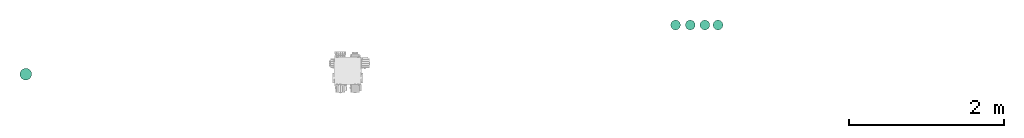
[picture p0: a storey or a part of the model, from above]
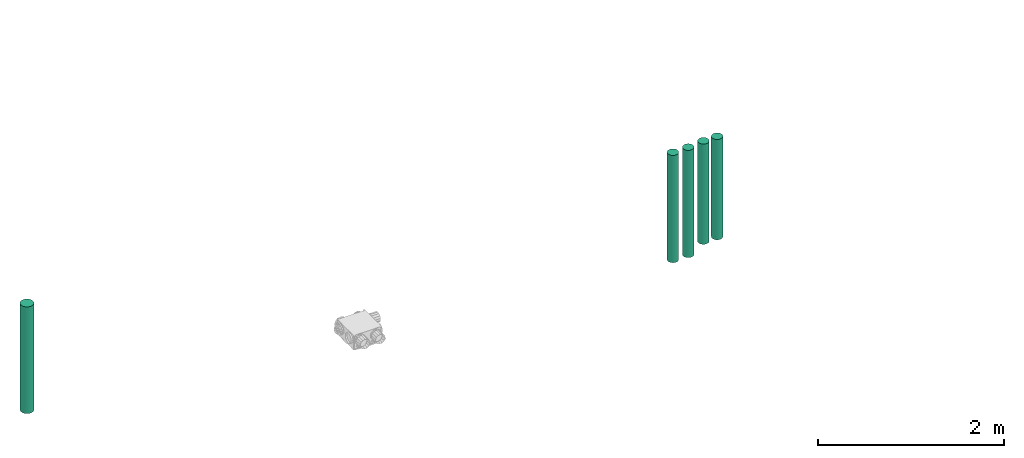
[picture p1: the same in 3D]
Properties of the parts of a building model (IFC4)

# File
Description: ViewDefinition [ReferenceView_V1.1]
File name: Project Number
Time: 2024-09-24T10:27:24
Written by: The EXPRESS Data Manager Version 5.02.0100.07 : 28 Aug 2013
Made in: 20191106_1200(x64) - Exporter 20.2.1.1 - Alternate UI 20.2.1.1
Comment: STEP Physical File produced by: The EXPRESS Data Manager Version 5.02.0100.07 : 28 Aug 2013 * Module: EDMstepFileFactory/EDMstandAlone * Creation date: Tue Sep 24 10:27:24 2024 * Host: RENSON-PC64rjMe * Database: C:\Users\naniw\AppData\Local\Temp\34e044a4-42ef-4c0d-bd3a-4a185e34024d\e22b095f-4d8d-4bd7-b097-9bfb5491500f\ifc * Database version: 5507 * Database creation date: Tue Sep 24 10:27:12 2024 * Schema: IFC4 * Model: DataRepository.ifc * Model creation date: Tue Sep 24 10:27:12 2024 * Header model: DataRepository.ifc_HeaderModel * Header model creation date: Tue Sep 24 10:27:12 2024 * EDMuser: sdai-user * EDMgroup: sdai-group * License ID and type: 5605 : Permanent license. Expiry date: * EDMstepFileFactory options: 020000

# IfcProject, Project Number
LongName: Project Name; Phase: Project Status

# IfcSite, Default
RefLatitude: 42, 12, 46, 799999; RefLongitude: -71, -1, -58, -799999; RefElevation: 0 mm

# IfcBuilding
Pset_BuildingCommon - Reference: Project Information; NumberOfStoreys: 4

# IfcBuildingStorey: Level:8mm Head (4)
Pset_BuildingStoreyCommon - Reference: 8mm Head
Name | LongName | Elevation (mm)
Level 1x | Level 1x | 0
Level 1 | Level 1 | 113.902
Position HB3 | Position HB3 | 1750
Level 1y | Level 1y | 2313.9

# IfcAirTerminalBox: Healthbox 3.0 - ceiling, Renson_Healthbox 3 Hygro+_Extraction_Unit:Healthbox 3.0 - ceiling:1049261
In: Position HB3
Type - Material: Color RGB 037-040-080, Color RGB 255-255-255
Type - Pset_AirTerminalBoxTypeCommon - Reference: Healthbox 3.0 - ceiling
Type - Pset_EnvironmentalImpactIndicators - Reference: Healthbox 3.0 - ceiling
Type - Pset_ManufacturerTypeInformation - Manufacturer: Renson
Pset_AirTerminalBoxTypeCommon - sets with these values: 2

# IfcAirTerminalBox: Healthbox 3.0 - wall attiek, Renson_Healthbox 3 Hygro+_Extraction_Unit:Healthbox 3.0 - wall attiek:1049051
In: Level 1x
Type - Material: Color RGB 037-040-080, Color RGB 255-255-255
Type - Pset_AirTerminalBoxTypeCommon - Reference: Healthbox 3.0 - wall attiek
Type - Pset_EnvironmentalImpactIndicators - Reference: Healthbox 3.0 - wall attiek
Type - Pset_ManufacturerTypeInformation - Manufacturer: Renson
Pset_AirTerminalBoxTypeCommon - sets with these values: 2

# IfcAirTerminalBox: Healthbox 3.0 - wall attiek 2, Renson_Healthbox 3 Hygro+_Extraction_Unit:Healthbox 3.0 - wall attiek 2:1060601
In: Level 1x
Type - Material: Color RGB 037-040-080, Color RGB 255-255-255
Type - Pset_AirTerminalBoxTypeCommon - Reference: Healthbox 3.0 - wall attiek 2
Type - Pset_EnvironmentalImpactIndicators - Reference: Healthbox 3.0 - wall attiek 2
Type - Pset_ManufacturerTypeInformation - Manufacturer: Renson
Pset_AirTerminalBoxTypeCommon - sets with these values: 2

# IfcAirTerminalBox: Healthbox 3.0 - wall wc (2)
Type - Material: Color RGB 037-040-080, Color RGB 255-255-255
Type - Pset_AirTerminalBoxTypeCommon - Reference: Healthbox 3.0 - wall wc
Type - Pset_EnvironmentalImpactIndicators - Reference: Healthbox 3.0 - wall wc
Type - Pset_ManufacturerTypeInformation - Manufacturer: Renson
Pset_AirTerminalBoxTypeCommon - sets with these values: 2
Name (Renson_Healthbox 3 Hygro+_Extraction_Unit:Healthbox 3.0 - wall wc:...) | In
1022833 | Level 1x
1059578 | Level 1

# IfcBuildingElementProxy: Model Text:120mm Arial (5)
In: Level 1x
Pset_BuildingElementProxyCommon - IsExternal: no; Reference: 120mm Arial
Pset_BuildingElementProxyProvisionForVoid - Depth: 10 mm
Pset_EnvironmentalImpactIndicators - Reference: 120mm Arial
Name (Model Text:120mm Arial:...) | Width (mm) | Height (mm)
1086742 | 10 | 15.0684
1086753 | 10 | 15.0684
1086783 | 10 | 15.0684
1086848 | 10 | 15.0684
1086858

# IfcBuildingElementProxy: Model Text:190mm Arial (5)
In: Level 1x
Pset_BuildingElementProxyCommon - Reference: 190mm Arial; IsExternal: no
Pset_BuildingElementProxyProvisionForVoid - Depth: 10 mm
Pset_EnvironmentalImpactIndicators - Reference: 190mm Arial
Name (Model Text:190mm Arial:...) | Width (mm) | Height (mm)
1086664 | 10 | 23.8584
1086681 | 10 | 23.8584
1086690 | 10 | 23.8584
1086699 | 10 | 23.8584
1086710

# IfcController: Bathroom Module (28)
Type - Classification: ﻿﻿ ​ ​ ​ ﻿ ​ ​ ﻿ ​ ​ ﻿ ​﻿ ​ ​ ﻿ ﻿﻿ (Uniformat); Material: Color RGB 037-040-080, Color RGB 255-255-255, Color RGB 040-040-040
Type - Pset_ControllerTypeCommon - Reference: Bathroom Module
Type - Pset_EnvironmentalImpactIndicators - Reference: Bathroom Module
Type - Pset_ManufacturerTypeInformation - Manufacturer: Renson
Pset_ControllerTypeCommon - sets with these values: 2
Name (Renson_Healthbox 3 Hygro+_Control Unit_Control Module:Bathroom Module:...) | In
1023607 | Level 1x
1032259 | Level 1x
1033093 | Level 1x
1033628 | Position HB3
1034343 | Level 1x
1034346 | Level 1x
1049052 | Level 1x
1049053 | Level 1x
1049262 | Position HB3
1049263 | Position HB3
1051230 | Position HB3
1052670 | Level 1y
1053146 | Level 1y
1053752 | Level 1x
1054423 | Level 1x
1059581 | Position HB3
1059586 | Level 1x
1059587 | Level 1x
1059600 | Level 1
1059601 | Level 1
1059943 | Level 1x
1081952 | Level 1x
1083636 | Level 1x
1083668 | Level 1x
1084480 | Level 1x
1084481 | Level 1x
1094915 | Level 1x
1094946 | Level 1x

# IfcCovering: Compound Ceiling:Plain (3)
In: Level 1
Type - PredefinedType: CEILING
Type - Pset_CoveringCommon - IsExternal: no; Reference: Plain; ThermalTransmittance: 0.549915 kg/K/s3
Type - Pset_EnvironmentalImpactIndicators - Reference: Plain
Material: Metal Stud Layer 45 mm, Gypsum Wall Board 12 mm; Group: Model Group:Renson_Ceiling_01 (members excluded):1088081
Name (Compound Ceiling:Plain:...)
1088362
1088379
1088469

# IfcCovering: Compound Ceiling:Transparent, Compound Ceiling:Transparent:1088462
In: Level 1
Type - PredefinedType: CEILING
Type - Pset_CoveringCommon - IsExternal: no; Reference: Transparent; ThermalTransmittance: 19.2982 kg/K/s3
Type - Pset_EnvironmentalImpactIndicators - Reference: Transparent
Material: Glass, Clear Glazing 57 mm; Group: Model Group:Renson_Ceiling_01 (members excluded):1088081

# IfcDuctFitting: 1.5 D (5)
In: Level 1x
Type - Pset_DuctFittingTypeCommon - Reference: 1.5 D
Type - Pset_EnvironmentalImpactIndicators - Reference: 1.5 D
Pset_DuctFittingTypeCommon - sets with these values: 2
Name (M_Round Elbow:1.5 D:...)
1048279
1059492
1059612
1064223
1086076

# IfcDuctFitting: 125 (2)
In: Level 1x
Type - Classification: ﻿﻿​ ﻿﻿﻿ ﻿ ﻿ ﻿ ﻿ ﻿ ﻿ ﻿ ﻿ ﻿ ﻿ ﻿ ​ ﻿ ﻿ ​ ​ ﻿ ﻿ ​﻿﻿ (Uniformat); Material: Color RGB 037-040-080
Type - Pset_DuctFittingTypeCommon - Reference: 125
Type - Pset_EnvironmentalImpactIndicators - Reference: 125
Type - Pset_ManufacturerTypeInformation - Manufacturer: Renson
Pset_DuctFittingTypeCommon - sets with these values: 2
Name
Renson_Easyflex_Round_Coupling_S:125:1080404
VE_Coupling_Round_MEPcontent_Renson_Easyflex_BE-EN_CP Shared:125:1081115

# IfcDuctFitting: 125 (2)
In: Level 1x
Type - PredefinedType: TRANSITION; Material: Color RAL 9002
Type - Pset_DuctFittingTypeCommon - Reference: 125
Type - Pset_EnvironmentalImpactIndicators - Reference: 125
Type - Pset_ManufacturerTypeInformation - Manufacturer: Renson
Pset_DuctFittingTypeCommon - sets with these values: 2
Name
Renson_Easyflex_Reducer_Oval to Round:125:1080402
Renson_Easyflex_Connection Piece_Oval to Round:125:1081114

# IfcDuctFitting: 125-150 (5)
Type - PredefinedType: TRANSITION; Classification: ﻿﻿ ​ ​ ​ ﻿ ​ ​ ﻿ ​ ​ ﻿ ​﻿ ​ ​ ﻿ ﻿﻿ (Uniformat); Material: Color RGB 037-040-080
Type - Pset_DuctFittingTypeCommon - Reference: 125-150
Type - Pset_EnvironmentalImpactIndicators - Reference: 125-150
Type - Pset_ManufacturerTypeInformation - Manufacturer: Renson
Pset_DuctFittingTypeCommon - sets with these values: 2
Name (Renson_Healthbox 3_Reducer_Round_Exhaust Adapter 125-150:125-150:...) | In
1022835 | Level 1x
1049055 | Level 1x
1049265 | Position HB3
1059579 | Position HB3
1060605 | Level 1x

# IfcDuctFitting: 135x55 Flat (4)
In: Level 1x
Type - Classification: ﻿﻿​ ﻿﻿﻿ ﻿ ﻿ ﻿ ﻿ ﻿ ﻿ ﻿ ﻿ ﻿ ﻿ ﻿ ​ ﻿ ﻿ ​ ​ ﻿ ﻿ ​﻿﻿ (Uniformat); Material: Color RGB 037-040-080
Type - Pset_DuctFittingTypeCommon - Reference: 135x55 Flat
Type - Pset_EnvironmentalImpactIndicators - Reference: 135x55 Flat
Type - Pset_ManufacturerTypeInformation - Manufacturer: Renson
Pset_DuctFittingTypeCommon - sets with these values: 2
Name
VE_Coupling_Oval_MEPcontent_Renson_Easyflex_Flat_BE-EN_CP Shared:135x55 Flat:1042776
VE_Coupling_Oval_MEPcontent_Renson_Easyflex_Flat_BE-EN_CP Shared:135x55 Flat:1059604
Renson_Easyflex_Flat_Coupling_Oval_S:135x55 Flat:1080403
VE_Coupling_Oval_MEPcontent_Renson_Easyflex_Flat_BE-EN_CP Shared:135x55 Flat:1081116

# IfcDuctFitting: 135x55 Quick Bracket (8)
In: Level 1x
Type - Material: Color RGB 037-040-080
Type - Pset_DuctFittingTypeCommon - Reference: 135x55 Quick Bracket
Type - Pset_EnvironmentalImpactIndicators - Reference: 135x55 Quick Bracket
Type - Pset_ManufacturerTypeInformation - Manufacturer: Renson
Pset_DuctFittingTypeCommon - sets with these values: 2
Name
VE_Bracket_MEPcontent_Renson_Easyflex_Quick_BE-EN_CP Shared:135x55 Quick Bracket:1042777
VE_Bracket_MEPcontent_Renson_Easyflex_Quick_BE-EN_CP Shared:135x55 Quick Bracket:1042778
VE_Bracket_MEPcontent_Renson_Easyflex_Quick_BE-EN_CP Shared:135x55 Quick Bracket:1059605
VE_Bracket_MEPcontent_Renson_Easyflex_Quick_BE-EN_CP Shared:135x55 Quick Bracket:1059606
Renson_Easyflex_Quick_Bracket_S:135x55 Quick Bracket:1080405
Renson_Easyflex_Quick_Bracket_S:135x55 Quick Bracket:1080406
VE_Bracket_MEPcontent_Renson_Easyflex_Quick_BE-EN_CP Shared:135x55 Quick Bracket:1081117
VE_Bracket_MEPcontent_Renson_Easyflex_Quick_BE-EN_CP Shared:135x55 Quick Bracket:1081118

# IfcDuctFitting: 80 (2)
In: Level 1x
Type - Classification: ﻿﻿​ ﻿﻿﻿ ﻿ ﻿ ﻿ ﻿ ﻿ ﻿ ﻿ ﻿ ﻿ ﻿ ﻿ ​ ﻿ ﻿ ​ ​ ﻿ ﻿ ​﻿﻿ (Uniformat); Material: Color RGB 037-040-080
Type - Pset_DuctFittingTypeCommon - Reference: 80
Type - Pset_EnvironmentalImpactIndicators - Reference: 80
Type - Pset_ManufacturerTypeInformation - Manufacturer: Renson
Pset_DuctFittingTypeCommon - sets with these values: 2
Name (VE_Coupling_Round_MEPcontent_Renson_Easyflex_BE-EN_CP Shared:80:...)
1042775
1059603

# IfcDuctFitting: 80 (2)
In: Level 1x
Type - PredefinedType: TRANSITION; Material: Color RAL 9002
Type - Pset_DuctFittingTypeCommon - Reference: 80
Type - Pset_EnvironmentalImpactIndicators - Reference: 80
Type - Pset_ManufacturerTypeInformation - Manufacturer: Renson
Pset_DuctFittingTypeCommon - sets with these values: 2
Name (Renson_Easyflex_Connection Piece_Oval to Round:80:...)
1042774
1059602

# IfcDuctFitting: 80-125 (30)
Type - PredefinedType: TRANSITION; Classification: ﻿﻿ ​ ​ ​ ﻿ ​ ​ ﻿ ​ ​ ﻿ ​﻿ ​ ​ ﻿ ﻿﻿ (Uniformat); Material: Color RGB 255-255-255
Type - Pset_DuctFittingTypeCommon - Reference: 80-125
Type - Pset_EnvironmentalImpactIndicators - Reference: 80-125
Type - Pset_ManufacturerTypeInformation - Manufacturer: Renson
Pset_DuctFittingTypeCommon - sets with these values: 2
Name (Renson_Healthbox 3_Reducer_Round_Adapter 80-125:80-125:...) | In
1022836 | Level 1x
1033125 | Level 1x
1033159 | Level 1x
1033627 | Level 1
1034193 | Level 1x
1049056 | Level 1x
1049057 | Level 1x
1049267 | Position HB3
1051115 | Position HB3
1051787 | Level 1x
1052456 | Level 1x
1053259 | Level 1y
1054508 | Level 1x
1055206 | Level 1x
1059580 | Level 1
1059588 | Level 1x
1059589 | Level 1x
1059595 | Position HB3
1060306 | Level 1x
1060606 | Level 1x
1060607 | Level 1x
1060609 | Level 1x
1061302 | Level 1x
1061360 | Level 1x
1064091 | Level 1y
1082111 | Level 1y
1083114 | Level 1x
1083689 | Level 1x
1084475 | Level 1x
1084482 | Level 1x

# IfcDuctFitting: With Print (3)
Type - PredefinedType: JUNCTION; Material: Color RGB 255-255-255, Color RGB 040-040-040
Type - Pset_DuctFittingTypeCommon - Reference: With Print
Type - Pset_EnvironmentalImpactIndicators - Reference: With Print
Type - Pset_ManufacturerTypeInformation - Manufacturer: Renson
Pset_DuctFittingTypeCommon - sets with these values: 2
Name | In
Renson_Healthbox 3_2-way Collector Piece_With Control Modules_Right_T_Round:With Print:1052668 | Level 1y
Renson_Healthbox 3_2-way Collector Piece_With Control Modules_Left_T_Round:With Print:1053750 | Level 1x
Renson_Healthbox 3_2-way Collector Piece_With Control Modules_Left_T_Round:With Print:1081423 | Level 1x

# IfcDuctFitting: Without Print (18)
Type - PredefinedType: JUNCTION; Material: Color RGB 255-255-255
Type - Pset_DuctFittingTypeCommon - Reference: Without Print
Type - Pset_EnvironmentalImpactIndicators - Reference: Without Print
Type - Pset_ManufacturerTypeInformation - Manufacturer: Renson
Pset_DuctFittingTypeCommon - sets with these values: 2
Name | In
Renson_Healthbox 3_2-way Collector Piece_With Control Modules_Left_T_Round:Without Print:1027976 | Level 1x
Renson_Healthbox 3_2-way Collector Piece_With Control Modules_Right_T_Round:Without Print:1032200 | Level 1x
Renson_Healthbox 3_2-way Collector Piece_With Control Modules_Left_T_Round:Without Print:1033358 | Level 1
Renson_Healthbox 3_2-way Collector Piece_With Control Modules_Right_T_Round:Without Print:1051310 | Level 1x
Renson_Healthbox 3_2-way Collector Piece_With Control Modules_Right_T_Round:Without Print:1053145 | Level 1y
Renson_Healthbox 3_2-way Collector Piece_With Control Modules_Left_T_Round:Without Print:1054421 | Level 1x
Renson_Healthbox 3_2-way Collector Piece_With Control Modules_Left_T_Round:Without Print:1055204 | Level 1x
Renson_Healthbox 3_2-way Collector Piece_With Control Modules_Left_T_Round:Without Print:1059582 | Level 1x
Renson_Healthbox 3_2-way Collector Piece_With Control Modules_Right_T_Round:Without Print:1059584 | Level 1x
Renson_Healthbox 3_2-way Collector Piece_With Control Modules_Right_T_Round:Without Print:1059941 | Level 1x
Renson_Healthbox 3_2-way Collector Piece_Without Control Modules_Left_T_Round:Without Print:1063686 | Level 1y
Renson_Healthbox 3_2-way Collector Piece_Without Control Modules_Left_T_Round:Without Print:1082109 | Level 1y
Renson_Healthbox 3_2-way Collector Piece_Without Control Modules_Left_T_Round:Without Print:1082351 | Level 1x
Renson_Healthbox 3_2-way Collector Piece_With Control Modules_Left_T_Round:Without Print:1083154 | Level 1x
Renson_Healthbox 3_2-way Collector Piece_With Control Modules_Left_T_Round:Without Print:1083341 | Level 1x
Renson_Healthbox 3_2-way Collector Piece_Without Control Modules_Left_T_Round:Without Print:1084473 | Level 1x
Renson_Healthbox 3_2-way Collector Piece_With Control Modules_Left_T_Round:Without Print:1084476 | Level 1x
Renson_Healthbox 3_2-way Collector Piece_With Control Modules_Left_T_Round:Without Print:1084478 | Level 1x

# IfcDuctSegment: Oval Duct:Easyflex Oval (3)
In: Level 1x
Type - Pset_DuctSegmentTypeCommon - Reference: Easyflex Oval
Type - Pset_EnvironmentalImpactIndicators - Reference: Easyflex Oval
Pset_DuctSegmentTypeCommon - sets with these values: 2
Name (Oval Duct:Easyflex Oval:...)
1048906
1059622
1080951

# IfcDuctSegment: Round Duct:Riser pipe (25)
Type - Pset_DuctSegmentTypeCommon - Reference: Riser pipe
Type - Pset_EnvironmentalImpactIndicators - Reference: Riser pipe
Type - Pset_ManufacturerTypeInformation - Manufacturer: Renson
Pset_DuctSegmentTypeCommon - sets with these values: 2
Name (Round Duct:Riser pipe:...) | In
1034252 | Level 1x
1034295 | Level 1x
1048244 | Level 1x
1048259 | Level 1x
1048568 | Level 1x
1048599 | Level 1x
1048634 | Level 1x
1048705 | Level 1x
1052340 | Level 1x
1056225 | Level 1x
1058840 | Position HB3
1058886 | Position HB3
1058917 | Position HB3
1058982 | Position HB3
1059019 | Level 1x
1059061 | Level 1x
1059596 | Level 1x
1059598 | Level 1x
1059608 | Level 1x
1059610 | Level 1x
1059614 | Level 1x
1059616 | Level 1x
1059618 | Level 1x
1059620 | Level 1x
1084663 | Position HB3

# IfcDuctSegment: Round Duct:Taps (12)
Type - Pset_DuctSegmentTypeCommon - Reference: Taps
Type - Pset_EnvironmentalImpactIndicators - Reference: Taps
Pset_DuctSegmentTypeCommon - sets with these values: 2
Name (Round Duct:Taps:...) | In
1059245 | Level 1x
1059484 | Level 1x
1060448 | Level 1x
1081298 | Level 1x
1083722 | Level 1x
1083758 | Level 1x
1084483 | Level 1x
1084485 | Level 1x
1093831 | Level 1y
1093877 | Level 1y
1096096 | Level 1x
1096130 | Level 1x

# IfcOpeningElement: Opening (27)
PredefinedType: OPENING
Pset_EnvironmentalImpactIndicators - sets with these values: 2
Name | In | Reference | Manufacturer
VE_Bracket_MEPcontent_Renson_Easyflex_Quick_BE-EN_CP Shared:135x55 Quick Bracket:1042777:1 | Level 1x | 135x55 Quick Bracket | Renson
VE_Bracket_MEPcontent_Renson_Easyflex_Quick_BE-EN_CP Shared:135x55 Quick Bracket:1042777:2 | Level 1x | 135x55 Quick Bracket | Renson
VE_Bracket_MEPcontent_Renson_Easyflex_Quick_BE-EN_CP Shared:135x55 Quick Bracket:1042777:3 | Level 1x | 135x55 Quick Bracket | Renson
VE_Bracket_MEPcontent_Renson_Easyflex_Quick_BE-EN_CP Shared:135x55 Quick Bracket:1042778:1 | Level 1x | 135x55 Quick Bracket | Renson
VE_Bracket_MEPcontent_Renson_Easyflex_Quick_BE-EN_CP Shared:135x55 Quick Bracket:1042778:2 | Level 1x | 135x55 Quick Bracket | Renson
VE_Bracket_MEPcontent_Renson_Easyflex_Quick_BE-EN_CP Shared:135x55 Quick Bracket:1042778:3 | Level 1x | 135x55 Quick Bracket | Renson
VE_Bracket_MEPcontent_Renson_Easyflex_Quick_BE-EN_CP Shared:135x55 Quick Bracket:1059605:1 | Level 1x | 135x55 Quick Bracket | Renson
VE_Bracket_MEPcontent_Renson_Easyflex_Quick_BE-EN_CP Shared:135x55 Quick Bracket:1059605:2 | Level 1x | 135x55 Quick Bracket | Renson
VE_Bracket_MEPcontent_Renson_Easyflex_Quick_BE-EN_CP Shared:135x55 Quick Bracket:1059605:3 | Level 1x | 135x55 Quick Bracket | Renson
VE_Bracket_MEPcontent_Renson_Easyflex_Quick_BE-EN_CP Shared:135x55 Quick Bracket:1059606:1 | Level 1x | 135x55 Quick Bracket | Renson
VE_Bracket_MEPcontent_Renson_Easyflex_Quick_BE-EN_CP Shared:135x55 Quick Bracket:1059606:2 | Level 1x | 135x55 Quick Bracket | Renson
VE_Bracket_MEPcontent_Renson_Easyflex_Quick_BE-EN_CP Shared:135x55 Quick Bracket:1059606:3 | Level 1x | 135x55 Quick Bracket | Renson
Renson_Easyflex_Quick_Bracket_S:135x55 Quick Bracket:1080405:1 | Level 1x | 135x55 Quick Bracket | Renson
Renson_Easyflex_Quick_Bracket_S:135x55 Quick Bracket:1080405:2 | Level 1x | 135x55 Quick Bracket | Renson
Renson_Easyflex_Quick_Bracket_S:135x55 Quick Bracket:1080405:3 | Level 1x | 135x55 Quick Bracket | Renson
Renson_Easyflex_Quick_Bracket_S:135x55 Quick Bracket:1080406:1 | Level 1x | 135x55 Quick Bracket | Renson
Renson_Easyflex_Quick_Bracket_S:135x55 Quick Bracket:1080406:2 | Level 1x | 135x55 Quick Bracket | Renson
Renson_Easyflex_Quick_Bracket_S:135x55 Quick Bracket:1080406:3 | Level 1x | 135x55 Quick Bracket | Renson
VE_Bracket_MEPcontent_Renson_Easyflex_Quick_BE-EN_CP Shared:135x55 Quick Bracket:1081117:1 | Level 1x | 135x55 Quick Bracket | Renson
VE_Bracket_MEPcontent_Renson_Easyflex_Quick_BE-EN_CP Shared:135x55 Quick Bracket:1081117:2 | Level 1x | 135x55 Quick Bracket | Renson
VE_Bracket_MEPcontent_Renson_Easyflex_Quick_BE-EN_CP Shared:135x55 Quick Bracket:1081117:3 | Level 1x | 135x55 Quick Bracket | Renson
VE_Bracket_MEPcontent_Renson_Easyflex_Quick_BE-EN_CP Shared:135x55 Quick Bracket:1081118:1 | Level 1x | 135x55 Quick Bracket | Renson
VE_Bracket_MEPcontent_Renson_Easyflex_Quick_BE-EN_CP Shared:135x55 Quick Bracket:1081118:2 | Level 1x | 135x55 Quick Bracket | Renson
VE_Bracket_MEPcontent_Renson_Easyflex_Quick_BE-EN_CP Shared:135x55 Quick Bracket:1081118:3 | Level 1x | 135x55 Quick Bracket | Renson
Basic Wall:Generic - 200mm:1087786 | Level 1 | Generic - 200mm | Group: Model Group:Renson_Ceiling_01 (members excluded):1088081
Basic Wall:Generic - 140mm Masonry:1087787 | Level 1 | Generic - 140mm Masonry | Group: Model Group:Renson_Ceiling_01 (members excluded):1088081
Basic Wall:Generic - 50mm (g):1087790 | Level 1y | Generic - 50mm (g) | Group: Model Group:Renson_Ceiling_01 (members excluded):1088081

# IfcRoof: Basic Roof:Generic - 140, Basic Roof:Generic - 140:1088435
In: Level 1y
Type - Pset_EnvironmentalImpactIndicators - Reference: Generic - 140
Type - Pset_RoofCommon - IsExternal: yes; Reference: Generic - 140
Material: Default Roof 140 mm; Group: Model Group:Renson_Ceiling_01 (members excluded):1088081

# IfcSlab: Floor:Generic 150mm (c) (5)
In: Level 1
Type - PredefinedType: FLOOR; Material: Default Floor 150 mm
Type - Pset_EnvironmentalImpactIndicators - Reference: Generic 150mm (c)
Type - Pset_ReinforcementBarPitchOfSlab - Reference: Generic 150mm (c)
Type - Pset_SlabCommon - IsExternal: no; Reference: Generic 150mm (c)
Pset_EnvironmentalImpactIndicators - sets with these values: 2
Pset_SlabCommon - LoadBearing: no
Group: Model Group:Renson_Ceiling_01 (members excluded):1088081
Name (Floor:Generic 150mm (c):...) | PitchAngle (deg)
1088328 | 0
1088337 | 0
1088346 | 0
1088355
1088372

# IfcSlab: Floor:Generic 150mm (g) (5)
In: Level 1y
Type - PredefinedType: FLOOR; Material: Glass, Clear Glazing 150 mm
Type - Pset_EnvironmentalImpactIndicators - Reference: Generic 150mm (g)
Type - Pset_ReinforcementBarPitchOfSlab - Reference: Generic 150mm (g)
Type - Pset_SlabCommon - IsExternal: no; Reference: Generic 150mm (g); ThermalTransmittance: 7.33333 kg/K/s3
Pset_EnvironmentalImpactIndicators - sets with these values: 2
Pset_SlabCommon - LoadBearing: no
Group: Model Group:Renson_Ceiling_01 (members excluded):1088081
Name (Floor:Generic 150mm (g):...)
1088405 | Pset_SlabCommon - PitchAngle: 0 deg
1088453
1088478
1088486
1088494 | Pset_SlabCommon - PitchAngle: 0 deg

# IfcWall: Basic Wall:Generic - 140mm Masonry (4)
In: Level 1
Type - Material: Concrete Masonry Units 140 mm
Type - Pset_EnvironmentalImpactIndicators - Reference: Generic - 140mm Masonry
Type - Pset_ReinforcementBarPitchOfWall - Reference: Generic - 140mm Masonry
Type - Pset_WallCommon - IsExternal: no; Reference: Generic - 140mm Masonry; ThermalTransmittance: 9.28571 kg/K/s3
Pset_EnvironmentalImpactIndicators - sets with these values: 2
Pset_WallCommon - IsExternal: yes; LoadBearing: no
Group: Model Group:Renson_Ceiling_01 (members excluded):1088081
Name (Basic Wall:Generic - 140mm Masonry:...) | ExtendToStructure
1088367 | no
1088368 | no
1088384 | yes
1088385 | no

# IfcWall: Basic Wall:Generic - 200mm (10)
Type - Material: Default Wall 200 mm
Type - Pset_EnvironmentalImpactIndicators - Reference: Generic - 200mm
Type - Pset_ReinforcementBarPitchOfWall - Reference: Generic - 200mm
Type - Pset_WallCommon - IsExternal: no; Reference: Generic - 200mm
Pset_EnvironmentalImpactIndicators - sets with these values: 2
Pset_WallCommon - IsExternal: yes; LoadBearing: no
Group: Model Group:Renson_Ceiling_01 (members excluded):1088081
Name (Basic Wall:Generic - 200mm:...) | In | ExtendToStructure
1088325 | Level 1 | yes
1088334 | Level 1 | no
1088343 | Level 1 | no
1088352 | Level 1 | no
1088369 | Level 1 | yes
1088411 | Level 1y | no
1088412 | Level 1y | no
1088483 | Level 1y | no
1088491 | Level 1y | no
1088500 | Level 1y | yes

# IfcWall: Basic Wall:Generic - 50mm (g), Basic Wall:Generic - 50mm (g):1088388
In: Level 1y
Type - Material: Glass, Clear Glazing 50 mm
Type - Pset_EnvironmentalImpactIndicators - Reference: Generic - 50mm (g)
Type - Pset_ReinforcementBarPitchOfWall - Reference: Generic - 50mm (g)
Type - Pset_WallCommon - IsExternal: no; Reference: Generic - 50mm (g); ThermalTransmittance: 22 kg/K/s3
Pset_EnvironmentalImpactIndicators - sets with these values: 2
Pset_WallCommon - IsExternal: yes; LoadBearing: no; ExtendToStructure: yes
Group: Model Group:Renson_Ceiling_01 (members excluded):1088081
